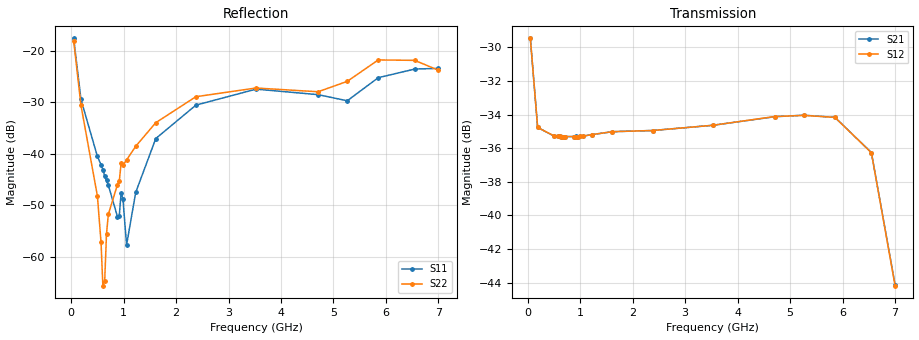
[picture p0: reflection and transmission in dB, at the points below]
! Integrated Device Technology
! Corporate Headquarters
! 6024 Silver Creek Valley Road
! San Jose, CA 95138  USA
! Phone:  1-408-284-8200
! Toll Free:  1-800-223-1366
! Webpage:  http://www.idt.com/
! Timing and RF Division
! 515 Groton Road, Suite 102
! Westford, MA 01886-6024
! Device:  F2258
! Description: Voltage Variable RF Attenuator
! Frequency:  50.0 -  6000.00 MHz
! Package:  3x3 mm Thin QFN Plastic Package: 16 pin
! Ports:  2 RF, 2 DC
!  Pin  1  = NC
!  Pin  2  = NC
!  Pin  3  = RF2  = Port 2
!  Pin  4  = GND
!  Pin  5  = Vdd
!  Pin  6  = NC
!  Pin  7  = VCTRL
!  Pin  8  = NC
!  Pin  9  = GND
!  Pin 10  = RF1  = Port 1
!  Pin 11  = NC
!  Pin 12  = NC
!  Pin 13  = NC
!  Pin 14  = NC
!  Pin 15  = NC
!  Pin 16  = NC
! Vcntrl:  2.150 Volts
! Vdd:  +3.300 Volts
! Current:  1.152 mA
! Data:  The device was measured on a the F2258 evaluation board which has
!  individual transmission lines to the RF pins.  Data was collected
!  using a calibrated network analyzer.  The evaluation board was
!  de-embedded using a TRL calibration technique.
!  The reference plane is the edge of the package pin.
! Misc:  SN 10
!  Action Tracker AT0285
! Date Measured:  2014-12-10
! Date:  2016-01-13  MJV
! Note:
!  Integrated Device Technology supplies this data as a sample of measured
!  data at the package pin for this product.  Your particular data for this
!  product may vary.
!  Data was taken at 25 degrees C.
!  Integrated Device Technology reserves the right to change this data at anytime.
!Freq_(GHz)  S11M_(dB)  S11P_(deg)  S21M_(dB)  S21P_(deg)  S12M_(dB)  S12P_(deg)  S22M_(dB)  S22P_(deg)
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# GHz S dB R 50
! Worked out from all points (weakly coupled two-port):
!   201 points, 50 MHz to 7 GHz, reference 50 ohm
!   highest |S21| = -29.47 dB at 50 MHz (marker M1); lowest = -44.1 dB at 7 GHz (marker M2)
!   lowest |S11| = -57.7 dB at 1.058 GHz (marker M3), VSWR 1.00, Z = 49.9 + j0.0576 ohm
!   |S11| at or under -10 dB: start of sweep to end of sweep
!   |S22| runs from -65.6 to -18.0 dB; largest |S21 - S12| = 9.4e-05
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0.05  -17.55 -111.0  -29.47 -67.9  -29.47 -68.0  -18.02 -110.5
0.189  -29.42 -109.4  -34.77 -24.5  -34.77 -24.5  -30.57 -103.3
0.50175  -40.47 -121.6  -35.28 -11.2  -35.27 -11.2  -48.15 -97.5
0.57125  -42.11 -124.6  -35.30 -10.4  -35.30 -10.4  -57.15 -84.8
0.606  -43.07 -126.1  -35.30 -10.0  -35.30 -10.0  -65.58 -63.8
0.64075  -44.24 -127.7  -35.31 -9.7  -35.31 -9.7  -64.70 25.3
0.6755  -45.12 -131.6  -35.31 -9.5  -35.31 -9.4  -55.52 56.8
0.71025  -46.06 -137.3  -35.31 -9.2  -35.31 -9.2  -51.73 76.8
0.884  -52.17 166.4  -35.31 -8.5  -35.31 -8.5  -45.96 83.0
0.91875  -52.01 150.5  -35.30 -8.4  -35.31 -8.4  -45.27 82.8
0.9535  -47.64 -162.5  -35.31 -8.3  -35.31 -8.3  -41.84 102.8
0.98825  -48.67 -174.3  -35.29 -8.2  -35.30 -8.2  -42.19 99.5
1.05775  -57.70 153.7  -35.28 -8.1  -35.28 -8.0  -41.16 83.3
1.2315  -47.48 46.4  -35.19 -8.0  -35.19 -8.0  -38.51 61.3
1.61375  -37.01 32.7  -35.02 -9.7  -35.02 -9.8  -33.93 42.9
2.37825  -30.52 48.1  -34.95 -13.4  -34.95 -13.4  -28.88 37.6
3.525  -27.41 91.6  -34.64 -19.9  -34.64 -19.9  -27.19 63.4
4.7065  -28.48 95.6  -34.13 -29.1  -34.12 -29.1  -27.92 54.9
5.2625  -29.67 54.3  -34.04 -35.2  -34.05 -35.2  -25.90 17.4
5.85325  -25.19 29.8  -34.17 -45.7  -34.17 -45.8  -21.74 -4.8
6.54825  -23.51 45.0  -36.26 -66.4  -36.27 -66.4  -21.82 -39.6
7  -23.38 84.4  -44.13 -62.1  -44.18 -61.6  -23.74 -129.3
